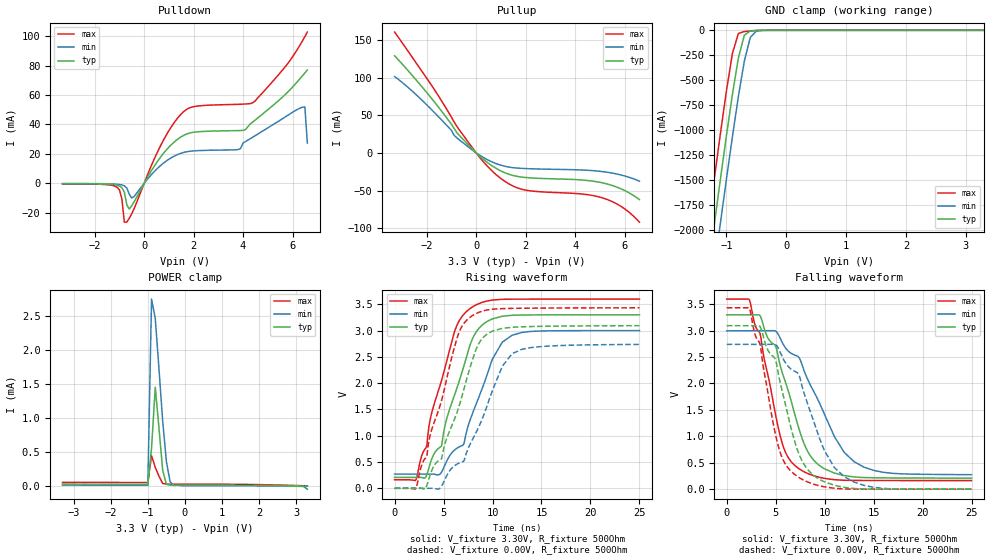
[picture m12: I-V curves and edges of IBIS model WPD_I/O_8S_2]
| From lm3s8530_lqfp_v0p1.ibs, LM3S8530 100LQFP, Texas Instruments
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[Model]   WPD_I/O_8S_2
Model_type   I/O
Vinl = 1.26
Vinh = 2.04
Vmeas = 1.65
| variable   typ   min   max
C_comp   9.739pF   9.739pF   9.739pF
[Model Spec]
Vinh+   1.91   1.78   2.04
Vinh-   1.90   1.76   2.03
Vinl+   1.40   1.27   1.54
Vinl-   1.39   1.26   1.53
| variable   typ   min   max
[Temperature Range]  25   85   -40
[Voltage Range]   3.3V   3.0V   3.6V
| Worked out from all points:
|   slope of the pulldown table from 0 to 0.495 V, typ, clamps not added: 35.8 ohm
|   slope of the pullup table from 0 to 0.495 V, typ, clamps not added: 35.8 ohm
|   GND clamp passes 1 mA (typ) near -0.48 V on its own axis
|   POWER clamp passes 1 mA (typ) near -0.72 V on its own axis
|   falling waveform, V_fixture 3.30V, R_fixture 500Ohm: 20-80 % time 2.94ns typ, 4.09ns min, 2.26ns max; typ from 3.3 V to 0.208 V
|   rising waveform, V_fixture 3.30V, R_fixture 500Ohm: 20-80 % time 2.82ns typ, 3.05ns min, 2.7ns max; typ from 0.208 V to 3.3 V
|   falling waveform, V_fixture 0.00V, R_fixture 500Ohm: 20-80 % time 2.56ns typ, 3.29ns min, 2.08ns max; typ from 3.09 V to 0 V
|   rising waveform, V_fixture 0.00V, R_fixture 500Ohm: 20-80 % time 3.14ns typ, 3.58ns min, 2.87ns max; typ from 0 V to 3.09 V
[Pulldown]
|  Voltage   I(typ)   I(min)   I(max)
-3.3V     -256.5uA   -145.6uA   -364.4uA
-1.1V     -1.273mA   -587.4uA   -2.566mA
-900mV    -2.885mA   -1.061mA   -10.54mA
-800mV    -5.992mA   -1.67mA    -26.39mA
-700mV    -14.71mA   -3.214mA   -26.32mA
-500mV    -15.25mA   -9.999mA   -20.65mA
600mV     16.35mA    11.13mA    23.4mA
1.5V      31.67mA    20.51mA    47.18mA
3.8V      35.87mA    22.99mA    53.71mA
4.4V      41.79mA    31.47mA    54.86mA
6.5V      75.05mA    51.94mA    99.75mA
6.6V      77.06mA    27.41mA    102.8mA
[Pullup]
|  Voltage   I(typ)   I(min)   I(max)
-3.3V     128.9mA    101.3mA    160.4mA
-2V       80.11mA    63.76mA    99.01mA
-1V       37.89mA    29.82mA    47.29mA
-700mV    23.8mA     17.69mA    31.26mA
300mV     -8.861mA   -6.312mA   -12.18mA
1V        -24.01mA   -16.38mA   -34.13mA
1.5V      -30.15mA   -19.7mA    -44.24mA
2V        -32.74mA   -20.87mA   -49.48mA
4.3V      -36.12mA   -22.8mA    -54.74mA
5.1V      -39.81mA   -24.88mA   -59.77mA
5.9V      -48.4mA    -29.75mA   -72.06mA
6.6V      -62.06mA   -37.61mA   -92.08mA
[GND Clamp]
|  Voltage   I(typ)   I(min)   I(max)
-3.3V     -11.72A    -12.12A    -11.3A
-1.4V     -2.845A    -3.285A    -2.387A
-1.3V     -2.39A     -2.831A    -1.93A
-1.2V     -1.938A    -2.38A     -1.478A
-1.1V     -1.494A    -1.934A    -1.036A
-1V       -1.059A    -1.496A    -610.6mA
-900mV    -645mA     -1.069A    -232.9mA
-800mV    -277.1mA   -664.4mA   -31.59mA
-700mV    -48.56mA   -306.6mA   -12.1mA
-600mV    -5.561mA   -70.2mA    -6.281mA
-500mV    -1.172mA   -7.88mA    -2.176mA
3.3V      16.11uA    11.84uA    29.77uA
[POWER Clamp]
|  Voltage   I(typ)   I(min)   I(max)
-3.3V     31.42uA    17.14uA    57.54uA
-1V       30.25uA    16.5uA     55.43uA
-900mV    557.3uA    2.746mA    449.1uA
-800mV    1.452mA    2.463mA    276.5uA
-700mV    854.2uA    1.726mA    147.8uA
-600mV    235.9uA    958.2uA    41.01uA
-500mV    28.31uA    363.4uA    30.71uA
-400mV    16.41uA    67.09uA    29.83uA
-300mV    16.12uA    11.84uA    29.79uA
3.1V      2.408uA    -920.8nA   9.197uA
3.2V      1.227uA    -3.925uA   7.474uA
3.3V      -104.7pA   -42.65uA   5.692uA
[Ramp]
| variable   typ   min   max
dV/dt_f   1.85/2.94n   1.63/4.09n   2.06/2.26n
dV/dt_r   1.85/3.14n   1.64/3.58n   2.06/2.87n
R_load = 500Ohm
[Falling Waveform]
V_fixture = 3.30V
V_fixture_min = 3.00V
V_fixture_max = 3.60V
R_fixture = 500Ohm
|   Time   V(typ)   V(min)   V(max)
0s        3.298V     2.996V     3.597V
2.3ns     3.298V     2.998V     3.592V
3.4ns     3.285V     2.998V     2.951V
5ns       2.706V     2.991V     1.401V
5.6ns     2.248V     2.805V     914.8mV
7.3ns     1.193V     2.509V     397.4mV
9.2ns     490.2mV    1.738V     237.3mV
11ns      304.1mV    994.2mV    179.2mV
13ns      231.5mV    521mV      165.4mV
25ns      208.4mV    274.1mV    162.4mV
[Rising Waveform]
V_fixture = 3.30V
V_fixture_min = 3.00V
V_fixture_max = 3.60V
R_fixture = 500Ohm
|   Time   V(typ)   V(min)   V(max)
0s        207.7mV    271.2mV    162.2mV
2.1ns     207.6mV    270.5mV    145.4mV
3.2ns     219.5mV    270.2mV    767.1mV
4.8ns     809.5mV    310.2mV    2.056V
6.1ns     1.764V     724.7mV    2.965V
7ns       2.281V     823mV      3.293V
7.7ns     2.72V      1.294V     3.417V
10ns      3.222V     2.461V     3.58V
12ns      3.29V      2.91V      3.596V
25ns      3.299V     2.999V     3.598V
[Falling Waveform]
V_fixture = 0.00V
V_fixture_min = 0.00V
V_fixture_max = 0.00V
R_fixture = 500Ohm
|   Time   V(typ)   V(min)   V(max)
0s        3.093V     2.739V     3.433V
2.3ns     3.093V     2.74V      3.428V
3.4ns     3.081V     2.74V      2.75V
5.3ns     2.158V     2.657V     795.1mV
7.1ns     811.9mV    2.216V     256.2mV
8.2ns     389.8mV    1.652V     141.9mV
10ns      137.8mV    724.8mV    43.49mV
12ns      34.21mV    235.5mV    4mV
16ns      400.8uV    14.31mV    285uV
25ns      39.28uV    92.37uV    23.51uV
[Rising Waveform]
V_fixture = 0.00V
V_fixture_min = 0.00V
V_fixture_max = 0.00V
R_fixture = 500Ohm
|   Time   V(typ)   V(min)   V(max)
0s        387uV      2.264mV    176uV
2.1ns     185.3uV    936.1uV    -16.2mV
3.2ns     13.7mV     510.2uV    580.9mV
4.6ns     539.8mV    -3.563mV   1.547V
6.4ns     1.457V     463.1mV    2.869V
7.8ns     2.356V     871.9mV    3.265V
9.2ns     2.896V     1.442V     3.381V
11ns      3.041V     2.321V     3.417V
12ns      3.062V     2.56V      3.421V
25ns      3.092V     2.736V     3.432V
